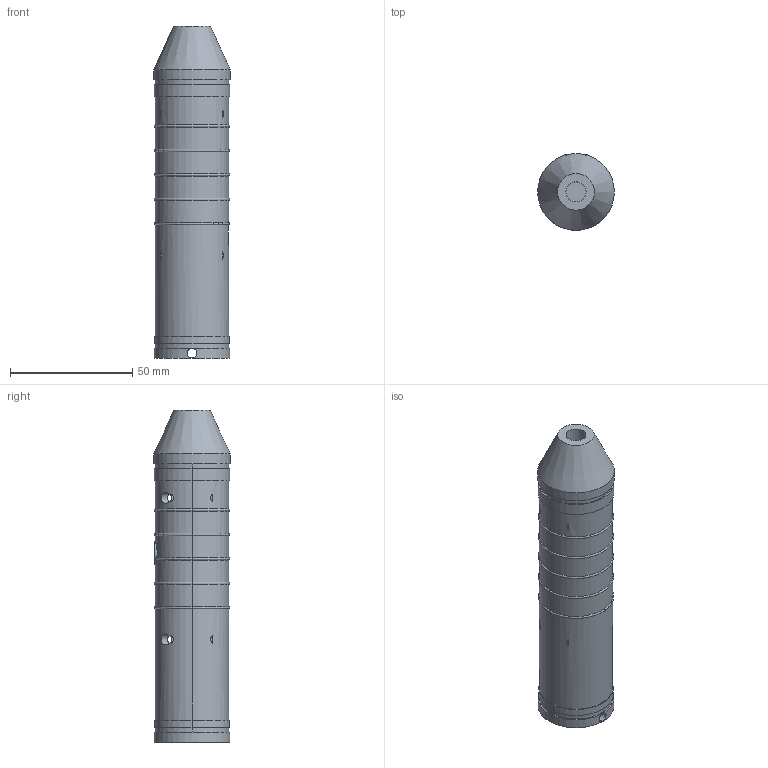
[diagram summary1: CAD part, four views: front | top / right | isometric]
STEP (ISO 10303-21) file: header records copied from the file, then geometry measured from it (millimetres).
FILE_DESCRIPTION(('Open CASCADE Model'),'2;1');
FILE_NAME('Open CASCADE Shape Model','2026-08-22T00:00:00',('Author'),( 'Open CASCADE'),'Open CASCADE STEP processor 7.8','build123d', 'Unknown');
FILE_SCHEMA(('AUTOMOTIVE_DESIGN { 1 0 10303 214 1 1 1 1 }'));
Length unit declared in the file: millimetre
Products named in the file (27): ASSEMBLY; MW-P-001A_UPPER_PRINTED_SHELL; MW-P-001B_LOWER_PRINTED_SHELL; MW-P-002_PCB_AND_BATTERY_CARRIER; SOLID; MW-P-003_REAR_CAP_WITH_LANYARD; MW-P-004_ROD_CONNECTOR_8MM; MW-P-005_PRESS_TO_ARM_PLUNGER
Assembly tree (26 placements, depth 4):
  ASSEMBLY
    MW-P-001A_UPPER_PRINTED_SHELL
    MW-P-001B_LOWER_PRINTED_SHELL
    MW-P-002_PCB_AND_BATTERY_CARRIER
      SOLID
      SOLID
      ASSEMBLY
        SOLID
      ASSEMBLY
        SOLID
      ASSEMBLY
        SOLID
      ASSEMBLY
        SOLID
      ASSEMBLY
        SOLID
      ASSEMBLY
        SOLID
      ASSEMBLY
        SOLID
      ASSEMBLY
        SOLID
      ASSEMBLY
        SOLID
    MW-P-003_REAR_CAP_WITH_LANYARD
    MW-P-004_ROD_CONNECTOR_8MM
    MW-P-005_PRESS_TO_ARM_PLUNGER
Bounding box: 31.4 x 31.4 x 136 mm (x, y, z)
Volume: 44288.8 mm3; surface area: 34517.4 mm2
Topology: 16 solids, 16 shells, 242 faces, 604 edges, 400 vertices
Faces by surface type: plane 155, cylinder 72, torus 12, cone 3
Full cylindrical faces by diameter (mm): 1.7 x4, 2.4 x4, 3.5 x1, 4.1 x1, 4.4 x3, 4.5 x4, 4.6 x1, 5.1 x1, 5.3 x3, 8.2 x1, 9.2 x2, 31.4 x1
Entity records: 26114 total; most frequent: CARTESIAN_POINT 13858, DIRECTION 2050, ORIENTED_EDGE 1210, PCURVE 1208, DEFINITIONAL_REPRESENTATION 1208, LINE 1038, VECTOR 1038, EDGE_CURVE 604
One B-rep face of a CAD part: STEP entity #26798.
In plain terms, the conical face has half-angle 24.492 degrees and reference radius 15.7 mm.
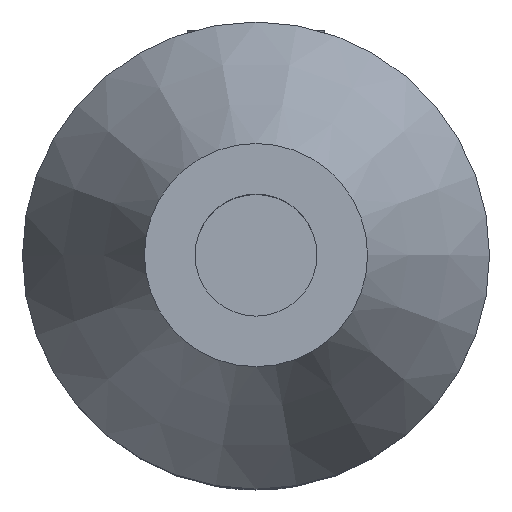
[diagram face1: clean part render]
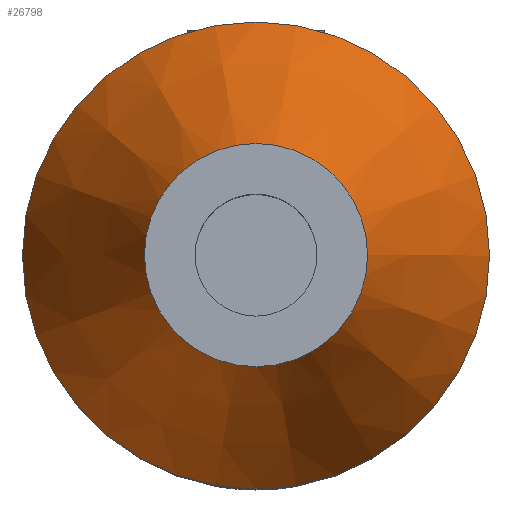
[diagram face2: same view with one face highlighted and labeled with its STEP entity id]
Its self-contained STEP definition (entity closure, numbers rounded to 3 decimals):
#26715 = EDGE_CURVE('',#26716,#26716,#26718,.T.);
#26716 = VERTEX_POINT('',#26717);
#26717 = CARTESIAN_POINT('',(15.7,0.,11.));
#26718 = SURFACE_CURVE('',#26719,(#26724,#26736),.PCURVE_S1.);
#26719 = CIRCLE('',#26720,15.7);
#26720 = AXIS2_PLACEMENT_3D('',#26721,#26722,#26723);
#26721 = CARTESIAN_POINT('',(0.,0.,11.));
#26722 = DIRECTION('',(0.,0.,1.));
#26723 = DIRECTION('',(1.,0.,0.));
#26724 = PCURVE('',#26725,#26730);
#26725 = CYLINDRICAL_SURFACE('',#26726,15.7);
#26726 = AXIS2_PLACEMENT_3D('',#26727,#26728,#26729);
#26727 = CARTESIAN_POINT('',(0.,0.,7.));
#26728 = DIRECTION('',(0.,0.,1.));
#26729 = DIRECTION('',(1.,0.,0.));
#26730 = DEFINITIONAL_REPRESENTATION('',(#26731),#26735);
#26731 = LINE('',#26732,#26733);
#26732 = CARTESIAN_POINT('',(0.,4.));
#26733 = VECTOR('',#26734,1.);
#26734 = DIRECTION('',(1.,0.));
#26735 = ( GEOMETRIC_REPRESENTATION_CONTEXT(2) 
PARAMETRIC_REPRESENTATION_CONTEXT() REPRESENTATION_CONTEXT('2D SPACE',''
  ) );
#26736 = PCURVE('',#26737,#26742);
#26737 = CONICAL_SURFACE('',#26738,15.7,0.427);
#26738 = AXIS2_PLACEMENT_3D('',#26739,#26740,#26741);
#26739 = CARTESIAN_POINT('',(0.,0.,11.));
#26740 = DIRECTION('',(0.,0.,-1.));
#26741 = DIRECTION('',(1.,0.,0.));
#26742 = DEFINITIONAL_REPRESENTATION('',(#26743),#26746);
#26743 = B_SPLINE_CURVE_WITH_KNOTS('',1,(#26744,#26745),.UNSPECIFIED.,
  .F.,.F.,(2,2),(0.,6.283),.PIECEWISE_BEZIER_KNOTS.);
#26744 = CARTESIAN_POINT('',(0.,0.));
#26745 = CARTESIAN_POINT('',(-6.283,0.));
#26746 = ( GEOMETRIC_REPRESENTATION_CONTEXT(2) 
PARAMETRIC_REPRESENTATION_CONTEXT() REPRESENTATION_CONTEXT('2D SPACE',''
  ) );
#26798 = ADVANCED_FACE('',(#26799),#26737,.T.);
#26799 = FACE_BOUND('',#26800,.T.);
#26800 = EDGE_LOOP('',(#26801,#26830,#26851,#26852));
#26801 = ORIENTED_EDGE('',*,*,#26802,.F.);
#26802 = EDGE_CURVE('',#26803,#26803,#26805,.T.);
#26803 = VERTEX_POINT('',#26804);
#26804 = CARTESIAN_POINT('',(7.5,0.,29.));
#26805 = SURFACE_CURVE('',#26806,(#26811,#26818),.PCURVE_S1.);
#26806 = CIRCLE('',#26807,7.5);
#26807 = AXIS2_PLACEMENT_3D('',#26808,#26809,#26810);
#26808 = CARTESIAN_POINT('',(0.,0.,29.));
#26809 = DIRECTION('',(0.,0.,1.));
#26810 = DIRECTION('',(1.,0.,0.));
#26811 = PCURVE('',#26737,#26812);
#26812 = DEFINITIONAL_REPRESENTATION('',(#26813),#26817);
#26813 = LINE('',#26814,#26815);
#26814 = CARTESIAN_POINT('',(-0.,-18.));
#26815 = VECTOR('',#26816,1.);
#26816 = DIRECTION('',(-1.,-0.));
#26817 = ( GEOMETRIC_REPRESENTATION_CONTEXT(2) 
PARAMETRIC_REPRESENTATION_CONTEXT() REPRESENTATION_CONTEXT('2D SPACE',''
  ) );
#26818 = PCURVE('',#26819,#26824);
#26819 = PLANE('',#26820);
#26820 = AXIS2_PLACEMENT_3D('',#26821,#26822,#26823);
#26821 = CARTESIAN_POINT('',(0.,0.,29.));
#26822 = DIRECTION('',(0.,0.,1.));
#26823 = DIRECTION('',(1.,0.,0.));
#26824 = DEFINITIONAL_REPRESENTATION('',(#26825),#26829);
#26825 = CIRCLE('',#26826,7.5);
#26826 = AXIS2_PLACEMENT_2D('',#26827,#26828);
#26827 = CARTESIAN_POINT('',(0.,0.));
#26828 = DIRECTION('',(1.,0.));
#26829 = ( GEOMETRIC_REPRESENTATION_CONTEXT(2) 
PARAMETRIC_REPRESENTATION_CONTEXT() REPRESENTATION_CONTEXT('2D SPACE',''
  ) );
#26830 = ORIENTED_EDGE('',*,*,#26831,.F.);
#26831 = EDGE_CURVE('',#26716,#26803,#26832,.T.);
#26832 = SEAM_CURVE('',#26833,(#26837,#26844),.PCURVE_S1.);
#26833 = LINE('',#26834,#26835);
#26834 = CARTESIAN_POINT('',(15.7,0.,11.));
#26835 = VECTOR('',#26836,1.);
#26836 = DIRECTION('',(-0.415,0.,0.91)
  );
#26837 = PCURVE('',#26737,#26838);
#26838 = DEFINITIONAL_REPRESENTATION('',(#26839),#26843);
#26839 = LINE('',#26840,#26841);
#26840 = CARTESIAN_POINT('',(-6.283,0.));
#26841 = VECTOR('',#26842,1.);
#26842 = DIRECTION('',(-0.,-1.));
#26843 = ( GEOMETRIC_REPRESENTATION_CONTEXT(2) 
PARAMETRIC_REPRESENTATION_CONTEXT() REPRESENTATION_CONTEXT('2D SPACE',''
  ) );
#26844 = PCURVE('',#26737,#26845);
#26845 = DEFINITIONAL_REPRESENTATION('',(#26846),#26850);
#26846 = LINE('',#26847,#26848);
#26847 = CARTESIAN_POINT('',(0.,-0.));
#26848 = VECTOR('',#26849,1.);
#26849 = DIRECTION('',(-0.,-1.));
#26850 = ( GEOMETRIC_REPRESENTATION_CONTEXT(2) 
PARAMETRIC_REPRESENTATION_CONTEXT() REPRESENTATION_CONTEXT('2D SPACE',''
  ) );
#26851 = ORIENTED_EDGE('',*,*,#26715,.T.);
#26852 = ORIENTED_EDGE('',*,*,#26831,.T.);
